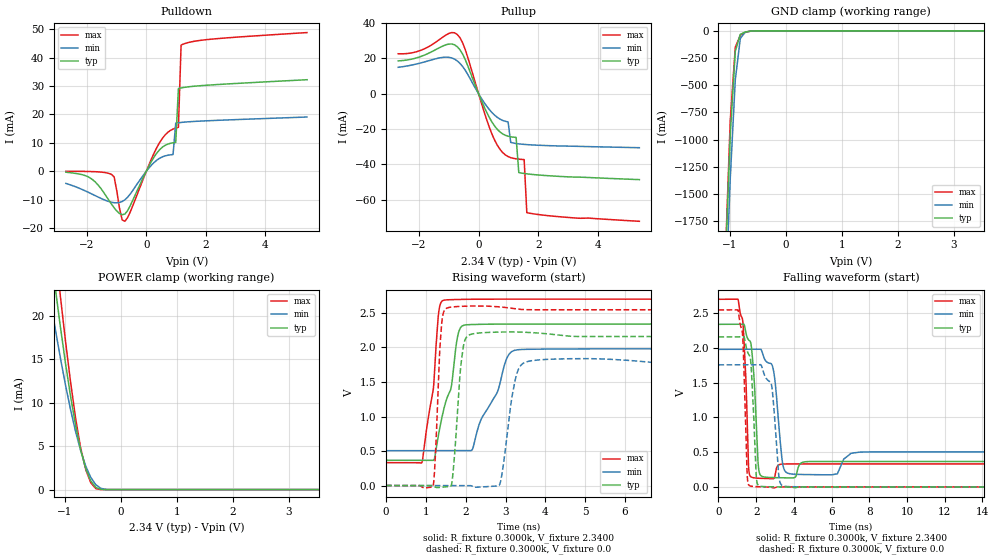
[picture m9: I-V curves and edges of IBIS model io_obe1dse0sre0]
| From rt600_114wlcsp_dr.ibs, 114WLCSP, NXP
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[Model] io_obe1dse0sre0
|   Model io_obe1dse0sre0
| Library cells for typ/min/max conditions are connected as defined below:
|  pad - External Pad
|  ipp_do - Core Input
|  ipp_obe - Output Buffer Enable
|  REFH3V3 - vdd1v8
|  REFL3V3 - REFL3V3
|  gnde - gnde
|  ipp_ina235_3v - NC
|  ipp_ina40_3v - NC
|  ipp_ina_mux - NC
|  ipp_ind - NC
|  ipp_ind_1p8v - NC
|  ipp_ind_3v - NC
|  vdd - vdd
|  vdd1v8 - vdd1v8
|  vdda - vdde3v3
|  vdde3v3 - vdde3v3
| All other pins connected to ground
Model_type I/O
Polarity   Non-Inverting
Enable   Active-High
Vinl =   0.7020V
Vinh =   1.6380V
Vmeas =  1.1700V
Cref =   25.0000pF
Rref =   0.5000k
Vref =   0.0V
C_comp   2.0776pF   1.9716pF   2.2888pF
[Temperature Range]   25.0000   0.1250k   -40.0000
[Voltage Range]   2.3400V   1.9800V   2.7000V
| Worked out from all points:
|   slope of the pulldown table from 0 to 0.351 V, typ, clamps not added: 55.2 ohm
|   slope of the pullup table from 0 to 0.351 V, typ, clamps not added: 26.8 ohm
|   GND clamp passes 1 mA (typ) near -0.56 V on its own axis
|   POWER clamp passes 1 mA (typ) near -0.54 V on its own axis
|   rising waveform, R_fixture 0.3000k, V_fixture 2.3400: 20-80 % time 415ps typ, 651ps min, 264ps max; typ from 0.366 V to 2.34 V
|   rising waveform, R_fixture 0.3000k, V_fixture 0.0: 20-80 % time 157ps typ, 243ps min, 112ps max; typ from 0 V to 2.16 V
|   falling waveform, R_fixture 0.3000k, V_fixture 2.3400: 20-80 % time 255ps typ, 316ps min, 204ps max; typ from 2.34 V to 0.366 V
|   falling waveform, R_fixture 0.3000k, V_fixture 0.0: 20-80 % time 219ps typ, 290ps min, 176ps max; typ from 2.16 V to 0 V
[Pulldown]
|Voltage   I(typ)   I(min)   I(max)
-2.7V     -300uA     -4.24mA    20uA
-1.89V    -2.28mA    -7.65mA    -70uA
-1.17V    -11.5mA    -10.86mA   -1.063mA
-1.08V    -12.8mA    -11.03mA   -1.914mA
-810mV    -15.25mA   -10.62mA   -17.03mA
-720mV    -15.01mA   -10.02mA   -17.56mA
270mV     5.141mA    3.175mA    6.578mA
900mV     10.04mA    5.902mA    14.86mA
990mV     10.18mA    16.92mA    15.22mA
1.08V     29.1mA     17.07mA    15.48mA
1.17V     29.31mA    17.18mA    44.37mA
5.4V      32.19mA    19.09mA    48.76mA
[Pullup]
|Voltage   I(typ)   I(min)   I(max)
-2.7V     18.65mA    15.02mA    22.69mA
-1.89V    21.45mA    17.72mA    24.97mA
-990mV    28.2mA     20.65mA    34.25mA
-630mV    25.02mA    17.31mA    31.88mA
630mV     -20.17mA   -13.38mA   -29.17mA
990mV     -24.01mA   -15.92mA   -35.55mA
1.08V     -24.34mA   -27.55mA   -36.16mA
1.26V     -24.7mA    -28.16mA   -36.84mA
1.35V     -44.61mA   -28.36mA   -37.03mA
1.53V     -45.13mA   -28.66mA   -37.28mA
1.62V     -45.34mA   -28.77mA   -67.33mA
5.4V      -48.61mA   -30.53mA   -72.22mA
[GND_clamp]
|Voltage   I(typ)   I(min)   I(max)
-2.7V     -30.44A    -30.24A    -31.41A
-1.08V    -2.185A    -2.567A    -2.12A
-990mV    -960.7mA   -1.36A     -827.1mA
-900mV    -189.4mA   -452.2mA   -151.9mA
-810mV    -32.32mA   -70.36mA   -40.6mA
-720mV    -10.56mA   -11.13mA   -13.17mA
-450mV    -34.64uA   -125.9uA   -17.93uA
5.4V      0A         0A         0A
[POWER_clamp]
|Voltage   I(typ)   I(min)   I(max)
-2.7V     98.14mA    78.02mA    112mA
-1.26V    27.63mA    21.78mA    33.04mA
-1.17V    23.01mA    18.34mA    27.46mA
-1.08V    18.61mA    15.06mA    22.08mA
-900mV    10.71mA    9.177mA    12.35mA
-810mV    7.362mA    6.657mA    8.175mA
-720mV    4.554mA    4.475mA    4.783mA
-630mV    2.426mA    2.705mA    2.314mA
-540mV    1.008mA    1.402mA    786.7uA
-450mV    256.5uA    565.2uA    114.6uA
-180mV    74.82nA    2.293uA    9.12nA
5.4V      0A         0A         0A
[Ramp]
| variable   typ   min   max
dV/dt_r  0.7331/0.1848n   0.4883/0.2609n   1.0536/0.1404n
dV/dt_f  0.8554/0.3903n   0.5138/0.4297n   0.4904/0.3011n
R_load = 50.0000
[Rising Waveform]
R_fixture= 0.3000k
V_fixture= 2.3400
V_fixture_min= 1.9800
V_fixture_max= 2.7000
|time   V(typ)   V(min)   V(max)
0s        366.2mV    504.9mV    331.6mV
892.9ps   366.2mV    504.9mV    328.7mV
1.202ns   373.4mV    504.9mV    1.52V
1.369ns   896.7mV    504.9mV    2.641V
1.633ns   1.418V     504.9mV    2.693V
1.817ns   2.215V     504.9mV    2.696V
2.096ns   2.331V     503.5mV    2.699V
3.085ns   2.34V      1.901V     2.701V
4.532ns   2.34V      1.98V      2.7V
500ns     2.34V      1.98V      2.7V
[Rising Waveform]
R_fixture= 0.3000k
V_fixture= 0.0
V_fixture_min= 0.0
V_fixture_max= 0.0
|time   V(typ)   V(min)   V(max)
0s        70.58nV    1.932uV    124.9nV
1.18ns    -5.717mV   1.921uV    -8.746mV
1.396ns   -24.7mV    1.832uV    2.354V
1.63ns    -5.895mV   1.53uV     2.585V
1.93ns    1.985V     -1.296uV   2.598V
2.241ns   2.204V     -24.29mV   2.602V
2.86ns    2.224V     26.29mV    2.588V
3.381ns   2.223V     1.74V      2.552V
5.009ns   2.159V     1.839V     2.547V
500ns     2.159V     1.757V     2.547V
[Falling Waveform]
R_fixture= 0.3000k
V_fixture= 2.3400
V_fixture_min= 1.9800
V_fixture_max= 2.7000
|time   V(typ)   V(min)   V(max)
0s        2.34V      1.98V      2.7V
1.274ns   2.339V     1.98V      2.411V
1.446ns   2.229V     1.98V      1.609V
1.589ns   2.118V     1.98V      323.7mV
1.695ns   2.087V     1.98V      152.7mV
2.145ns   230.8mV    1.98V      125mV
2.874ns   134.9mV    1.73V      118.5mV
3.488ns   131.7mV    249.2mV    330.4mV
5.764ns   366.5mV    174.5mV    331.7mV
500ns     366.2mV    504.9mV    331.6mV
[Falling Waveform]
R_fixture= 0.3000k
V_fixture= 0.0
V_fixture_min= 0.0
V_fixture_max= 0.0
|time   V(typ)   V(min)   V(max)
0s        2.159V     1.757V     2.547V
1.258ns   2.159V     1.757V     2.241V
1.575ns   1.921V     1.757V     45.51mV
1.73ns    1.745V     1.757V     10.75mV
2.041ns   68.94mV    1.757V     3.431mV
2.781ns   2.43mV     1.498V     -4.136mV
2.944ns   1.932mV    1.118V     -13.02mV
3.337ns   1.324mV    30.34mV    691.7uV
6.42ns    218.9uV    -5.477mV   16.26uV
500ns     1.115uV    3.189uV    739.6nV
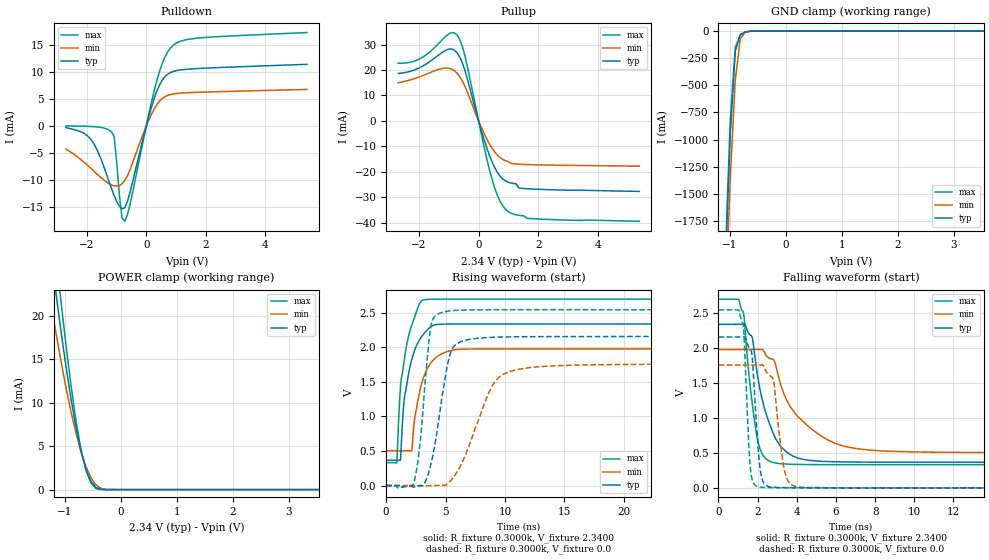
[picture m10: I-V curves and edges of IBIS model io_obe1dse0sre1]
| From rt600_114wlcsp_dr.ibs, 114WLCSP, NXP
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[Model] io_obe1dse0sre1
|   Model io_obe1dse0sre1
| Library cells for typ/min/max conditions are connected as defined below:
|  pad - External Pad
|  ipp_do - Core Input
|  ipp_obe - Output Buffer Enable
|  REFH3V3 - vdd1v8
|  REFL3V3 - REFL3V3
|  gnde - gnde
|  ipp_ina235_3v - NC
|  ipp_ina40_3v - NC
|  ipp_ina_mux - NC
|  ipp_ind - NC
|  ipp_ind_1p8v - NC
|  ipp_ind_3v - NC
|  ipp_sre - vdd
|  vdd - vdd
|  vdd1v8 - vdd1v8
|  vdda - vdde3v3
|  vdde3v3 - vdde3v3
| All other pins connected to ground
Model_type I/O
Polarity   Non-Inverting
Enable   Active-High
Vinl =   0.7020V
Vinh =   1.6380V
Vmeas =  1.1700V
Cref =   25.0000pF
Rref =   0.5000k
Vref =   0.0V
C_comp   2.0775pF   1.9715pF   2.2887pF
[Temperature Range]   25.0000   0.1250k   -40.0000
[Voltage Range]   2.3400V   1.9800V   2.7000V
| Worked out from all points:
|   slope of the pulldown table from 0 to 0.351 V, typ, clamps not added: 55.2 ohm
|   slope of the pullup table from 0 to 0.351 V, typ, clamps not added: 26.8 ohm
|   GND clamp passes 1 mA (typ) near -0.56 V on its own axis
|   POWER clamp passes 1 mA (typ) near -0.54 V on its own axis
|   rising waveform, R_fixture 0.3000k, V_fixture 2.3400: 20-80 % time 1.05ns typ, 1.14ns min, 967ps max; typ from 0.366 V to 2.34 V
|   rising waveform, R_fixture 0.3000k, V_fixture 0.0: 20-80 % time 1.21ns typ, 2.37ns min, 778ps max; typ from 0 V to 2.16 V
|   falling waveform, R_fixture 0.3000k, V_fixture 2.3400: 20-80 % time 994ps typ, 1.97ns min, 549ps max; typ from 2.34 V to 0.366 V
|   falling waveform, R_fixture 0.3000k, V_fixture 0.0: 20-80 % time 303ps typ, 428ps min, 239ps max; typ from 2.16 V to 0 V
[Pulldown]
|Voltage   I(typ)   I(min)   I(max)
-2.7V     -300uA     -4.24mA    20uA
-1.89V    -2.28mA    -7.65mA    -70uA
-1.17V    -11.5mA    -10.86mA   -1.063mA
-1.08V    -12.8mA    -11.03mA   -1.914mA
-810mV    -15.25mA   -10.62mA   -17.03mA
-720mV    -15.01mA   -10.02mA   -17.56mA
-540mV    -12.09mA   -7.995mA   -14.33mA
270mV     5.141mA    3.175mA    6.578mA
540mV     8.479mA    5.085mA    11.58mA
810mV     9.842mA    5.8mA      14.36mA
1.62V     10.56mA    6.191mA    16.13mA
5.4V      11.37mA    6.74mA     17.22mA
[Pullup]
|Voltage   I(typ)   I(min)   I(max)
-2.7V     18.65mA    15.02mA    22.69mA
-1.98V    20.9mA     17.32mA    24.39mA
-1.17V    27.29mA    20.7mA     32.48mA
-900mV    28.22mA    20.3mA     34.69mA
-720mV    26.73mA    18.68mA    33.68mA
-450mV    19.46mA    13.38mA    25.13mA
90mV      -3.666mA   -2.475mA   -5.026mA
450mV     -16.03mA   -10.65mA   -22.86mA
720mV     -21.64mA   -14.35mA   -31.5mA
990mV     -24.01mA   -15.92mA   -35.55mA
1.71V     -26.67mA   -17.16mA   -38.29mA
5.4V      -27.67mA   -17.75mA   -39.39mA
[GND_clamp]
|Voltage   I(typ)   I(min)   I(max)
-2.7V     -30.44A    -30.24A    -31.41A
-1.08V    -2.185A    -2.567A    -2.12A
-990mV    -960.7mA   -1.36A     -827.1mA
-900mV    -189.4mA   -452.2mA   -151.9mA
-810mV    -32.32mA   -70.36mA   -40.6mA
-720mV    -10.56mA   -11.13mA   -13.17mA
-450mV    -34.64uA   -125.9uA   -17.93uA
5.4V      0A         0A         0A
[POWER_clamp]
|Voltage   I(typ)   I(min)   I(max)
-2.7V     98.14mA    78.02mA    112mA
-1.26V    27.63mA    21.78mA    33.04mA
-1.17V    23.01mA    18.34mA    27.46mA
-1.08V    18.61mA    15.06mA    22.08mA
-900mV    10.71mA    9.177mA    12.35mA
-810mV    7.362mA    6.657mA    8.175mA
-720mV    4.554mA    4.475mA    4.783mA
-630mV    2.426mA    2.705mA    2.314mA
-540mV    1.008mA    1.402mA    786.7uA
-450mV    256.5uA    565.2uA    114.6uA
-180mV    74.82nA    2.293uA    9.12nA
5.4V      0A         0A         0A
[Ramp]
| variable   typ   min   max
dV/dt_r  0.7331/2.6104n   0.5023/5.1387n   1.0536/1.7615n
dV/dt_f  0.3185/1.8936n   0.1860/2.5156n   0.4882/1.0965n
R_load = 50.0000
[Rising Waveform]
R_fixture= 0.3000k
V_fixture= 2.3400
V_fixture_min= 1.9800
V_fixture_max= 2.7000
|time   V(typ)   V(min)   V(max)
0s        366.2mV    504.9mV    331.6mV
895.6ps   366.2mV    504.9mV    330mV
1.247ns   497.6mV    504.9mV    1.508V
1.524ns   1.257V     504.9mV    1.829V
2.142ns   1.817V     506mV      2.316V
2.378ns   1.949V     946.5mV    2.43V
2.747ns   2.093V     1.3V       2.612V
3.588ns   2.277V     1.732V     2.697V
7.967ns   2.34V      1.979V     2.7V
500ns     2.34V      1.98V      2.7V
[Rising Waveform]
R_fixture= 0.3000k
V_fixture= 0.0
V_fixture_min= 0.0
V_fixture_max= 0.0
|time   V(typ)   V(min)   V(max)
0s        70.58nV    1.932uV    124.9nV
2.291ns   -4.893mV   -24.67mV   26.57mV
2.781ns   -1.715mV   -10.34mV   494.7mV
3.259ns   42.72mV    -4.627mV   1.46V
3.936ns   437.3mV    -1.461mV   2.41V
5.277ns   1.839V     41.61mV    2.528V
6.322ns   2.085V     307mV      2.541V
9.536ns   2.15V      1.575V     2.546V
16.92ns   2.159V     1.748V     2.547V
500ns     2.159V     1.757V     2.547V
[Falling Waveform]
R_fixture= 0.3000k
V_fixture= 2.3400
V_fixture_min= 1.9800
V_fixture_max= 2.7000
|time   V(typ)   V(min)   V(max)
0s        2.34V      1.98V      2.7V
1.032ns   2.34V      1.98V      2.701V
1.272ns   2.339V     1.98V      2.511V
1.778ns   2.059V     1.98V      1.083V
2.211ns   1.289V     1.981V     499.3mV
3.002ns   664.7mV    1.659V     351.5mV
4.123ns   420.9mV    1.002V     334.8mV
6.774ns   369.6mV    575.3mV    331.8mV
13.25ns   366.2mV    506.7mV    331.7mV
500ns     366.2mV    504.9mV    331.6mV
[Falling Waveform]
R_fixture= 0.3000k
V_fixture= 0.0
V_fixture_min= 0.0
V_fixture_max= 0.0
|time   V(typ)   V(min)   V(max)
0s        2.159V     1.757V     2.547V
1.032ns   2.159V     1.757V     2.548V
1.256ns   2.159V     1.757V     2.342V
1.557ns   2.011V     1.757V     561.1mV
1.672ns   1.964V     1.757V     183.1mV
2.138ns   246.9mV    1.757V     9.93mV
2.7ns     12.31mV    1.591V     2.761mV
3.492ns   3.284mV    135.1mV    749.9uV
5.054ns   768uV      4.125mV    85.87uV
500ns     1.118uV    3.192uV    760.8nV
